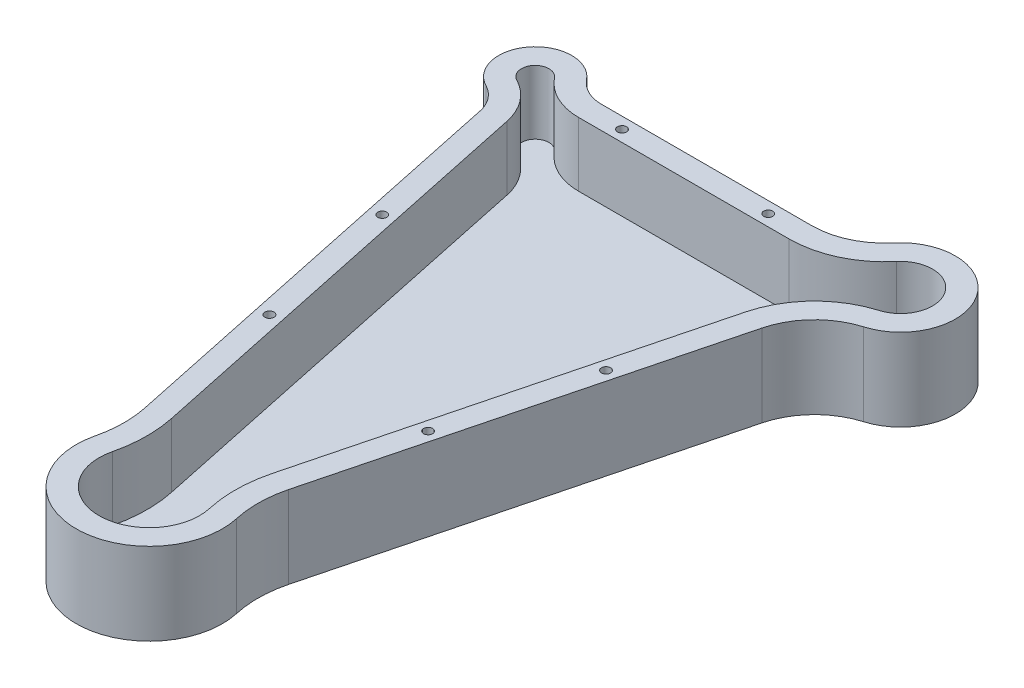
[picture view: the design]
ISO-10303-21;
HEADER;
FILE_DESCRIPTION(('STEP AP214'),'2;1');
FILE_NAME('part.step','',(''),(''),'','','');
FILE_SCHEMA(('AUTOMOTIVE_DESIGN { 1 0 10303 214 1 1 1 1 }'));
ENDSEC;
DATA;
#1=APPLICATION_CONTEXT('core data for automotive mechanical design processes');
#2=APPLICATION_PROTOCOL_DEFINITION('international standard','automotive_design',2000,#1);
#3=PRODUCT_CONTEXT('',#1,'mechanical');
#4=PRODUCT('Part','Part','',(#3));
#5=PRODUCT_RELATED_PRODUCT_CATEGORY('part','',(#4));
#6=PRODUCT_DEFINITION_FORMATION('','',#4);
#7=PRODUCT_DEFINITION_CONTEXT('part definition',#1,'design');
#8=PRODUCT_DEFINITION('design','',#6,#7);
#9=PRODUCT_DEFINITION_SHAPE('','',#8);
#10=(LENGTH_UNIT() NAMED_UNIT(*) SI_UNIT(.MILLI.,.METRE.));
#11=(NAMED_UNIT(*) PLANE_ANGLE_UNIT() SI_UNIT($,.RADIAN.));
#12=(NAMED_UNIT(*) SI_UNIT($,.STERADIAN.) SOLID_ANGLE_UNIT());
#13=UNCERTAINTY_MEASURE_WITH_UNIT(LENGTH_MEASURE(1.E-05),#10,'distance_accuracy_value','');
#14=(GEOMETRIC_REPRESENTATION_CONTEXT(3) GLOBAL_UNCERTAINTY_ASSIGNED_CONTEXT((#13)) GLOBAL_UNIT_ASSIGNED_CONTEXT((#10,
#11,#12)) REPRESENTATION_CONTEXT('',''));
#15=CARTESIAN_POINT('',(0.,0.,0.));
#16=DIRECTION('',(0.,0.,1.));
#17=DIRECTION('',(1.,0.,0.));
#18=AXIS2_PLACEMENT_3D('',#15,#16,#17);
#19=CARTESIAN_POINT('',(-73.1240495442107,12.7,-174.662274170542));
#20=DIRECTION('',(0.,-1.,0.));
#21=DIRECTION('',(0.,0.,-1.));
#22=AXIS2_PLACEMENT_3D('',#19,#20,#21);
#23=CYLINDRICAL_SURFACE('',#22,25.4);
#24=CARTESIAN_POINT('',(-73.1240495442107,0.,-174.662274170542));
#25=DIRECTION('',(0.,-1.,0.));
#26=DIRECTION('',(0.,0.,1.));
#27=AXIS2_PLACEMENT_3D('',#24,#25,#26);
#28=CIRCLE('',#27,25.4);
#29=CARTESIAN_POINT('',(-73.1240495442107,0.,-149.262274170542));
#30=VERTEX_POINT('',#29);
#31=CARTESIAN_POINT('',(-92.9519181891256,0.,-158.787274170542));
#32=VERTEX_POINT('',#31);
#33=EDGE_CURVE('E474',#30,#32,#28,.T.);
#34=ORIENTED_EDGE('',*,*,#33,.T.);
#35=DIRECTION('',(0.,-1.,0.));
#36=VECTOR('',#35,1.);
#37=CARTESIAN_POINT('',(-92.9519181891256,12.7,-158.787274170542));
#38=LINE('',#37,#36);
#39=CARTESIAN_POINT('',(-92.9519181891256,57.15,-158.787274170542));
#40=VERTEX_POINT('',#39);
#41=EDGE_CURVE('E12',#40,#32,#38,.T.);
#42=ORIENTED_EDGE('',*,*,#41,.F.);
#43=CARTESIAN_POINT('',(-73.1240495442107,57.15,-174.662274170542));
#44=DIRECTION('',(0.,-1.,0.));
#45=DIRECTION('',(0.,0.,1.));
#46=AXIS2_PLACEMENT_3D('',#43,#44,#45);
#47=CIRCLE('',#46,25.4);
#48=CARTESIAN_POINT('',(-73.1240495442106,57.15,-149.262274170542));
#49=VERTEX_POINT('',#48);
#50=EDGE_CURVE('E471',#49,#40,#47,.T.);
#51=ORIENTED_EDGE('',*,*,#50,.F.);
#52=DIRECTION('',(0.,-1.,0.));
#53=VECTOR('',#52,1.);
#54=CARTESIAN_POINT('',(-73.1240495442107,12.7,-149.262274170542));
#55=LINE('',#54,#53);
#56=EDGE_CURVE('E499',#49,#30,#55,.T.);
#57=ORIENTED_EDGE('',*,*,#56,.T.);
#58=EDGE_LOOP('',(#34,#42,#51,#57));
#59=FACE_BOUND('',#58,.T.);
#60=ADVANCED_FACE('F105',(#59),#23,.F.);
#61=CARTESIAN_POINT('',(-112.77978683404,12.7,-142.912274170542));
#62=DIRECTION('',(0.,-1.,0.));
#63=DIRECTION('',(0.,0.,-1.));
#64=AXIS2_PLACEMENT_3D('',#61,#62,#63);
#65=CYLINDRICAL_SURFACE('',#64,25.4);
#66=CARTESIAN_POINT('',(-112.77978683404,0.,-142.912274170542));
#67=DIRECTION('',(0.,1.,0.));
#68=DIRECTION('',(0.,0.,-1.));
#69=AXIS2_PLACEMENT_3D('',#66,#67,#68);
#70=CIRCLE('',#69,25.4);
#71=CARTESIAN_POINT('',(-124.432703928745,0.,-120.343057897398));
#72=VERTEX_POINT('',#71);
#73=EDGE_CURVE('E477',#32,#72,#70,.T.);
#74=ORIENTED_EDGE('',*,*,#73,.T.);
#75=DIRECTION('',(0.,-1.,0.));
#76=VECTOR('',#75,1.);
#77=CARTESIAN_POINT('',(-124.432703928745,12.7,-120.343057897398));
#78=LINE('',#77,#76);
#79=CARTESIAN_POINT('',(-124.432703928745,57.15,-120.343057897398));
#80=VERTEX_POINT('',#79);
#81=EDGE_CURVE('E112',#80,#72,#78,.T.);
#82=ORIENTED_EDGE('',*,*,#81,.F.);
#83=CARTESIAN_POINT('',(-112.77978683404,57.15,-142.912274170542));
#84=DIRECTION('',(0.,1.,0.));
#85=DIRECTION('',(0.,0.,1.));
#86=AXIS2_PLACEMENT_3D('',#83,#84,#85);
#87=CIRCLE('',#86,25.4);
#88=EDGE_CURVE('E438',#40,#80,#87,.T.);
#89=ORIENTED_EDGE('',*,*,#88,.F.);
#90=ORIENTED_EDGE('',*,*,#41,.T.);
#91=EDGE_LOOP('',(#74,#82,#89,#90));
#92=FACE_BOUND('',#91,.T.);
#93=ADVANCED_FACE('F579',(#92),#65,.T.);
#94=CARTESIAN_POINT('',(-136.08562102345,12.7,-97.7738416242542));
#95=DIRECTION('',(0.,-1.,0.));
#96=DIRECTION('',(0.,0.,-1.));
#97=AXIS2_PLACEMENT_3D('',#94,#95,#96);
#98=CYLINDRICAL_SURFACE('',#97,25.4);
#99=CARTESIAN_POINT('',(-136.08562102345,0.,-97.7738416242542));
#100=DIRECTION('',(0.,-1.,0.));
#101=DIRECTION('',(0.,0.,-1.));
#102=AXIS2_PLACEMENT_3D('',#99,#100,#101);
#103=CIRCLE('',#102,25.4);
#104=CARTESIAN_POINT('',(-111.23256360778,0.,-103.016506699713));
#105=VERTEX_POINT('',#104);
#106=EDGE_CURVE('E479',#72,#105,#103,.T.);
#107=ORIENTED_EDGE('',*,*,#106,.T.);
#108=DIRECTION('',(0.,-1.,0.));
#109=VECTOR('',#108,1.);
#110=CARTESIAN_POINT('',(-111.23256360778,12.7,-103.016506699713));
#111=LINE('',#110,#109);
#112=CARTESIAN_POINT('',(-111.23256360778,57.15,-103.016506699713));
#113=VERTEX_POINT('',#112);
#114=EDGE_CURVE('E526',#113,#105,#111,.T.);
#115=ORIENTED_EDGE('',*,*,#114,.F.);
#116=CARTESIAN_POINT('',(-136.08562102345,57.15,-97.7738416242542));
#117=DIRECTION('',(0.,-1.,0.));
#118=DIRECTION('',(0.,0.,1.));
#119=AXIS2_PLACEMENT_3D('',#116,#117,#118);
#120=CIRCLE('',#119,25.4);
#121=EDGE_CURVE('E441',#80,#113,#120,.T.);
#122=ORIENTED_EDGE('',*,*,#121,.F.);
#123=ORIENTED_EDGE('',*,*,#81,.T.);
#124=EDGE_LOOP('',(#107,#115,#122,#123));
#125=FACE_BOUND('',#124,.T.);
#126=ADVANCED_FACE('F532',(#125),#98,.F.);
#127=CARTESIAN_POINT('',(-111.23256360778,12.7,-103.016506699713));
#128=DIRECTION('',(0.978466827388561,0.,-0.206404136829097));
#129=DIRECTION('',(-0.206404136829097,0.,-0.978466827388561));
#130=AXIS2_PLACEMENT_3D('',#127,#128,#129);
#131=PLANE('',#130);
#132=DIRECTION('',(0.206404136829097,0.,0.978466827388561));
#133=VECTOR('',#132,1.);
#134=CARTESIAN_POINT('',(-111.23256360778,0.,-103.016506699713));
#135=LINE('',#134,#133);
#136=CARTESIAN_POINT('',(-48.879605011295,0.,192.570115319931));
#137=VERTEX_POINT('',#136);
#138=EDGE_CURVE('E481',#105,#137,#135,.T.);
#139=ORIENTED_EDGE('',*,*,#138,.T.);
#140=DIRECTION('',(0.,-1.,0.));
#141=VECTOR('',#140,1.);
#142=CARTESIAN_POINT('',(-48.879605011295,12.7,192.570115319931));
#143=LINE('',#142,#141);
#144=CARTESIAN_POINT('',(-48.879605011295,57.15,192.570115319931));
#145=VERTEX_POINT('',#144);
#146=EDGE_CURVE('E523',#145,#137,#143,.T.);
#147=ORIENTED_EDGE('',*,*,#146,.F.);
#148=DIRECTION('',(0.206404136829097,0.,0.978466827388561));
#149=VECTOR('',#148,1.);
#150=CARTESIAN_POINT('',(-111.23256360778,57.15,-103.016506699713));
#151=LINE('',#150,#149);
#152=EDGE_CURVE('E444',#113,#145,#151,.T.);
#153=ORIENTED_EDGE('',*,*,#152,.F.);
#154=ORIENTED_EDGE('',*,*,#114,.T.);
#155=EDGE_LOOP('',(#139,#147,#153,#154));
#156=FACE_BOUND('',#155,.T.);
#157=ADVANCED_FACE('F542',(#156),#131,.F.);
#158=CARTESIAN_POINT('',(-123.438777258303,12.7,208.298110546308));
#159=DIRECTION('',(0.,-1.,0.));
#160=DIRECTION('',(0.,0.,-1.));
#161=AXIS2_PLACEMENT_3D('',#158,#159,#160);
#162=CYLINDRICAL_SURFACE('',#161,76.2);
#163=CARTESIAN_POINT('',(-123.438777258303,0.,208.298110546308));
#164=DIRECTION('',(0.,-1.,0.));
#165=DIRECTION('',(0.,0.,1.));
#166=AXIS2_PLACEMENT_3D('',#163,#164,#165);
#167=CIRCLE('',#166,76.2);
#168=CARTESIAN_POINT('',(-49.3755109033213,0.,226.216608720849));
#169=VERTEX_POINT('',#168);
#170=EDGE_CURVE('E483',#137,#169,#167,.T.);
#171=ORIENTED_EDGE('',*,*,#170,.T.);
#172=DIRECTION('',(0.,-1.,0.));
#173=VECTOR('',#172,1.);
#174=CARTESIAN_POINT('',(-49.3755109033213,12.7,226.216608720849));
#175=LINE('',#174,#173);
#176=CARTESIAN_POINT('',(-49.3755109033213,57.15,226.216608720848));
#177=VERTEX_POINT('',#176);
#178=EDGE_CURVE('E520',#177,#169,#175,.T.);
#179=ORIENTED_EDGE('',*,*,#178,.F.);
#180=CARTESIAN_POINT('',(-123.438777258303,57.15,208.298110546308));
#181=DIRECTION('',(0.,-1.,0.));
#182=DIRECTION('',(0.,0.,1.));
#183=AXIS2_PLACEMENT_3D('',#180,#181,#182);
#184=CIRCLE('',#183,76.2);
#185=EDGE_CURVE('E447',#145,#177,#184,.T.);
#186=ORIENTED_EDGE('',*,*,#185,.F.);
#187=ORIENTED_EDGE('',*,*,#146,.T.);
#188=EDGE_LOOP('',(#171,#179,#186,#187));
#189=FACE_BOUND('',#188,.T.);
#190=ADVANCED_FACE('F546',(#189),#162,.F.);
#191=CARTESIAN_POINT('',(0.,12.7,238.162274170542));
#192=DIRECTION('',(0.,-1.,0.));
#193=DIRECTION('',(0.,0.,-1.));
#194=AXIS2_PLACEMENT_3D('',#191,#192,#193);
#195=CYLINDRICAL_SURFACE('',#194,50.8);
#196=CARTESIAN_POINT('',(0.,0.,238.162274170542));
#197=DIRECTION('',(0.,1.,0.));
#198=DIRECTION('',(0.,0.,-1.));
#199=AXIS2_PLACEMENT_3D('',#196,#197,#198);
#200=CIRCLE('',#199,50.8);
#201=CARTESIAN_POINT('',(49.5738798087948,0.,227.068562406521));
#202=VERTEX_POINT('',#201);
#203=EDGE_CURVE('E485',#169,#202,#200,.T.);
#204=ORIENTED_EDGE('',*,*,#203,.T.);
#205=DIRECTION('',(0.,-1.,0.));
#206=VECTOR('',#205,1.);
#207=CARTESIAN_POINT('',(49.5738798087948,12.7,227.068562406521));
#208=LINE('',#207,#206);
#209=CARTESIAN_POINT('',(49.5738798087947,57.15,227.068562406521));
#210=VERTEX_POINT('',#209);
#211=EDGE_CURVE('E517',#210,#202,#208,.T.);
#212=ORIENTED_EDGE('',*,*,#211,.F.);
#213=CARTESIAN_POINT('',(0.,57.15,238.162274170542));
#214=DIRECTION('',(0.,1.,0.));
#215=DIRECTION('',(0.,0.,1.));
#216=AXIS2_PLACEMENT_3D('',#213,#214,#215);
#217=CIRCLE('',#216,50.8);
#218=EDGE_CURVE('E450',#177,#210,#217,.T.);
#219=ORIENTED_EDGE('',*,*,#218,.F.);
#220=ORIENTED_EDGE('',*,*,#178,.T.);
#221=EDGE_LOOP('',(#204,#212,#219,#220));
#222=FACE_BOUND('',#221,.T.);
#223=ADVANCED_FACE('F553',(#222),#195,.T.);
#224=CARTESIAN_POINT('',(123.934699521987,12.7,210.42799476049));
#225=DIRECTION('',(0.,-1.,0.));
#226=DIRECTION('',(0.,0.,-1.));
#227=AXIS2_PLACEMENT_3D('',#224,#225,#226);
#228=CYLINDRICAL_SURFACE('',#227,76.2);
#229=CARTESIAN_POINT('',(123.934699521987,0.,210.42799476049));
#230=DIRECTION('',(0.,-1.,0.));
#231=DIRECTION('',(0.,0.,-1.));
#232=AXIS2_PLACEMENT_3D('',#229,#230,#231);
#233=CIRCLE('',#232,76.2);
#234=CARTESIAN_POINT('',(50.134019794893,0.,191.456972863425));
#235=VERTEX_POINT('',#234);
#236=EDGE_CURVE('E487',#202,#235,#233,.T.);
#237=ORIENTED_EDGE('',*,*,#236,.T.);
#238=DIRECTION('',(0.,-1.,0.));
#239=VECTOR('',#238,1.);
#240=CARTESIAN_POINT('',(50.134019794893,12.7,191.456972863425));
#241=LINE('',#240,#239);
#242=CARTESIAN_POINT('',(50.134019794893,57.15,191.456972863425));
#243=VERTEX_POINT('',#242);
#244=EDGE_CURVE('E514',#243,#235,#241,.T.);
#245=ORIENTED_EDGE('',*,*,#244,.F.);
#246=CARTESIAN_POINT('',(123.934699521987,57.15,210.42799476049));
#247=DIRECTION('',(0.,-1.,0.));
#248=DIRECTION('',(0.,0.,1.));
#249=AXIS2_PLACEMENT_3D('',#246,#247,#248);
#250=CIRCLE('',#249,76.2);
#251=EDGE_CURVE('E453',#210,#243,#250,.T.);
#252=ORIENTED_EDGE('',*,*,#251,.F.);
#253=ORIENTED_EDGE('',*,*,#211,.T.);
#254=EDGE_LOOP('',(#237,#245,#252,#253));
#255=FACE_BOUND('',#254,.T.);
#256=ADVANCED_FACE('F556',(#255),#228,.F.);
#257=CARTESIAN_POINT('',(50.1340197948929,12.7,191.456972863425));
#258=DIRECTION('',(-0.968512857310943,0.,-0.248963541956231));
#259=DIRECTION('',(-0.248963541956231,0.,0.968512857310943));
#260=AXIS2_PLACEMENT_3D('',#257,#258,#259);
#261=PLANE('',#260);
#262=DIRECTION('',(0.248963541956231,0.,-0.968512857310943));
#263=VECTOR('',#262,1.);
#264=CARTESIAN_POINT('',(50.1340197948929,0.,191.456972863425));
#265=LINE('',#264,#263);
#266=CARTESIAN_POINT('',(117.438914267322,0.,-70.3711451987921));
#267=VERTEX_POINT('',#266);
#268=EDGE_CURVE('E489',#235,#267,#265,.T.);
#269=ORIENTED_EDGE('',*,*,#268,.T.);
#270=DIRECTION('',(0.,-1.,0.));
#271=VECTOR('',#270,1.);
#272=CARTESIAN_POINT('',(117.438914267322,12.7,-70.3711451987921));
#273=LINE('',#272,#271);
#274=CARTESIAN_POINT('',(117.438914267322,57.15,-70.3711451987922));
#275=VERTEX_POINT('',#274);
#276=EDGE_CURVE('E511',#275,#267,#273,.T.);
#277=ORIENTED_EDGE('',*,*,#276,.F.);
#278=DIRECTION('',(0.248963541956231,0.,-0.968512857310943));
#279=VECTOR('',#278,1.);
#280=CARTESIAN_POINT('',(50.134019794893,57.15,191.456972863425));
#281=LINE('',#280,#279);
#282=EDGE_CURVE('E456',#243,#275,#281,.T.);
#283=ORIENTED_EDGE('',*,*,#282,.F.);
#284=ORIENTED_EDGE('',*,*,#244,.T.);
#285=EDGE_LOOP('',(#269,#277,#283,#284));
#286=FACE_BOUND('',#285,.T.);
#287=ADVANCED_FACE('F561',(#286),#261,.F.);
#288=CARTESIAN_POINT('',(166.639367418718,12.7,-57.7237972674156));
#289=DIRECTION('',(0.,-1.,0.));
#290=DIRECTION('',(0.,0.,-1.));
#291=AXIS2_PLACEMENT_3D('',#288,#289,#290);
#292=CYLINDRICAL_SURFACE('',#291,50.8);
#293=CARTESIAN_POINT('',(166.639367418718,0.,-57.7237972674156));
#294=DIRECTION('',(0.,-1.,0.));
#295=DIRECTION('',(0.,0.,1.));
#296=AXIS2_PLACEMENT_3D('',#293,#294,#295);
#297=CIRCLE('',#296,50.8);
#298=CARTESIAN_POINT('',(152.114136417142,0.,-106.402926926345));
#299=VERTEX_POINT('',#298);
#300=EDGE_CURVE('E491',#267,#299,#297,.T.);
#301=ORIENTED_EDGE('',*,*,#300,.T.);
#302=DIRECTION('',(0.,-1.,0.));
#303=VECTOR('',#302,1.);
#304=CARTESIAN_POINT('',(152.114136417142,12.7,-106.402926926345));
#305=LINE('',#304,#303);
#306=CARTESIAN_POINT('',(152.114136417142,57.15,-106.402926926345));
#307=VERTEX_POINT('',#306);
#308=EDGE_CURVE('E508',#307,#299,#305,.T.);
#309=ORIENTED_EDGE('',*,*,#308,.F.);
#310=CARTESIAN_POINT('',(166.639367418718,57.15,-57.7237972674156));
#311=DIRECTION('',(0.,-1.,0.));
#312=DIRECTION('',(0.,0.,1.));
#313=AXIS2_PLACEMENT_3D('',#310,#311,#312);
#314=CIRCLE('',#313,50.8);
#315=EDGE_CURVE('E459',#275,#307,#314,.T.);
#316=ORIENTED_EDGE('',*,*,#315,.F.);
#317=ORIENTED_EDGE('',*,*,#276,.T.);
#318=EDGE_LOOP('',(#301,#309,#316,#317));
#319=FACE_BOUND('',#318,.T.);
#320=ADVANCED_FACE('F565',(#319),#292,.F.);
#321=CARTESIAN_POINT('',(141.22021316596,12.7,-142.912274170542));
#322=DIRECTION('',(0.,-1.,0.));
#323=DIRECTION('',(0.,0.,-1.));
#324=AXIS2_PLACEMENT_3D('',#321,#322,#323);
#325=CYLINDRICAL_SURFACE('',#324,38.1);
#326=CARTESIAN_POINT('',(141.22021316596,0.,-142.912274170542));
#327=DIRECTION('',(0.,1.,0.));
#328=DIRECTION('',(0.,0.,1.));
#329=AXIS2_PLACEMENT_3D('',#326,#327,#328);
#330=CIRCLE('',#329,38.1);
#331=CARTESIAN_POINT('',(112.036143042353,0.,-167.405131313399));
#332=VERTEX_POINT('',#331);
#333=EDGE_CURVE('E493',#299,#332,#330,.T.);
#334=ORIENTED_EDGE('',*,*,#333,.T.);
#335=DIRECTION('',(0.,-1.,0.));
#336=VECTOR('',#335,1.);
#337=CARTESIAN_POINT('',(112.036143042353,12.7,-167.405131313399));
#338=LINE('',#337,#336);
#339=CARTESIAN_POINT('',(112.036143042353,57.15,-167.405131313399));
#340=VERTEX_POINT('',#339);
#341=EDGE_CURVE('E505',#340,#332,#338,.T.);
#342=ORIENTED_EDGE('',*,*,#341,.F.);
#343=CARTESIAN_POINT('',(141.22021316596,57.15,-142.912274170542));
#344=DIRECTION('',(0.,1.,0.));
#345=DIRECTION('',(0.,0.,1.));
#346=AXIS2_PLACEMENT_3D('',#343,#344,#345);
#347=CIRCLE('',#346,38.1);
#348=EDGE_CURVE('E462',#307,#340,#347,.T.);
#349=ORIENTED_EDGE('',*,*,#348,.F.);
#350=ORIENTED_EDGE('',*,*,#308,.T.);
#351=EDGE_LOOP('',(#334,#342,#349,#350));
#352=FACE_BOUND('',#351,.T.);
#353=ADVANCED_FACE('F569',(#352),#325,.T.);
#354=CARTESIAN_POINT('',(73.1240495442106,12.7,-200.062274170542));
#355=DIRECTION('',(0.,-1.,0.));
#356=DIRECTION('',(0.,0.,-1.));
#357=AXIS2_PLACEMENT_3D('',#354,#355,#356);
#358=CYLINDRICAL_SURFACE('',#357,50.8);
#359=CARTESIAN_POINT('',(73.1240495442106,0.,-200.062274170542));
#360=DIRECTION('',(0.,-1.,0.));
#361=DIRECTION('',(0.,0.,-1.));
#362=AXIS2_PLACEMENT_3D('',#359,#360,#361);
#363=CIRCLE('',#362,50.8);
#364=CARTESIAN_POINT('',(73.1240495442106,0.,-149.262274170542));
#365=VERTEX_POINT('',#364);
#366=EDGE_CURVE('E495',#332,#365,#363,.T.);
#367=ORIENTED_EDGE('',*,*,#366,.T.);
#368=DIRECTION('',(0.,-1.,0.));
#369=VECTOR('',#368,1.);
#370=CARTESIAN_POINT('',(73.1240495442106,12.7,-149.262274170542));
#371=LINE('',#370,#369);
#372=CARTESIAN_POINT('',(73.1240495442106,57.15,-149.262274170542));
#373=VERTEX_POINT('',#372);
#374=EDGE_CURVE('E502',#373,#365,#371,.T.);
#375=ORIENTED_EDGE('',*,*,#374,.F.);
#376=CARTESIAN_POINT('',(73.1240495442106,57.15,-200.062274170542));
#377=DIRECTION('',(0.,-1.,0.));
#378=DIRECTION('',(0.,0.,1.));
#379=AXIS2_PLACEMENT_3D('',#376,#377,#378);
#380=CIRCLE('',#379,50.8);
#381=EDGE_CURVE('E465',#340,#373,#380,.T.);
#382=ORIENTED_EDGE('',*,*,#381,.F.);
#383=ORIENTED_EDGE('',*,*,#341,.T.);
#384=EDGE_LOOP('',(#367,#375,#382,#383));
#385=FACE_BOUND('',#384,.T.);
#386=ADVANCED_FACE('F572',(#385),#358,.F.);
#387=CARTESIAN_POINT('',(73.1240495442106,12.7,-149.262274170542));
#388=DIRECTION('',(0.,0.,1.));
#389=DIRECTION('',(1.,0.,0.));
#390=AXIS2_PLACEMENT_3D('',#387,#388,#389);
#391=PLANE('',#390);
#392=DIRECTION('',(-1.,0.,0.));
#393=VECTOR('',#392,1.);
#394=CARTESIAN_POINT('',(73.1240495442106,0.,-149.262274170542));
#395=LINE('',#394,#393);
#396=EDGE_CURVE('E497',#365,#30,#395,.T.);
#397=ORIENTED_EDGE('',*,*,#396,.T.);
#398=ORIENTED_EDGE('',*,*,#56,.F.);
#399=DIRECTION('',(-1.,0.,0.));
#400=VECTOR('',#399,1.);
#401=CARTESIAN_POINT('',(73.1240495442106,57.15,-149.262274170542));
#402=LINE('',#401,#400);
#403=EDGE_CURVE('E468',#373,#49,#402,.T.);
#404=ORIENTED_EDGE('',*,*,#403,.F.);
#405=ORIENTED_EDGE('',*,*,#374,.T.);
#406=EDGE_LOOP('',(#397,#398,#404,#405));
#407=FACE_BOUND('',#406,.T.);
#408=ADVANCED_FACE('F575',(#407),#391,.F.);
#409=CARTESIAN_POINT('',(-73.1240495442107,0.,-174.662274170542));
#410=DIRECTION('',(0.,1.,0.));
#411=DIRECTION('',(0.,0.,1.));
#412=AXIS2_PLACEMENT_3D('',#409,#410,#411);
#413=PLANE('',#412);
#414=ORIENTED_EDGE('',*,*,#33,.F.);
#415=ORIENTED_EDGE('',*,*,#396,.F.);
#416=ORIENTED_EDGE('',*,*,#366,.F.);
#417=ORIENTED_EDGE('',*,*,#333,.F.);
#418=ORIENTED_EDGE('',*,*,#300,.F.);
#419=ORIENTED_EDGE('',*,*,#268,.F.);
#420=ORIENTED_EDGE('',*,*,#236,.F.);
#421=ORIENTED_EDGE('',*,*,#203,.F.);
#422=ORIENTED_EDGE('',*,*,#170,.F.);
#423=ORIENTED_EDGE('',*,*,#138,.F.);
#424=ORIENTED_EDGE('',*,*,#106,.F.);
#425=ORIENTED_EDGE('',*,*,#73,.F.);
#426=EDGE_LOOP('',(#414,#415,#416,#417,#418,#419,#420,#421,#422,#423,#424,#425));
#427=FACE_BOUND('',#426,.T.);
#428=ADVANCED_FACE('F538',(#427),#413,.F.);
#429=CARTESIAN_POINT('',(-112.77978683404,57.15,-142.912274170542));
#430=DIRECTION('',(0.,1.,0.));
#431=DIRECTION('',(0.,0.,1.));
#432=AXIS2_PLACEMENT_3D('',#429,#430,#431);
#433=PLANE('',#432);
#434=CARTESIAN_POINT('',(-50.8,57.15,-141.324774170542));
#435=DIRECTION('',(0.,1.,0.));
#436=DIRECTION('',(0.,0.,1.));
#437=AXIS2_PLACEMENT_3D('',#434,#435,#436);
#438=CIRCLE('',#437,3.17499999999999);
#439=CARTESIAN_POINT('',(-50.8,57.15,-138.149774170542));
#440=VERTEX_POINT('',#439);
#441=EDGE_CURVE('E756',#440,#440,#438,.T.);
#442=ORIENTED_EDGE('',*,*,#441,.F.);
#443=EDGE_LOOP('',(#442));
#444=FACE_BOUND('',#443,.T.);
#445=CARTESIAN_POINT('',(50.8,57.15,-141.324774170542));
#446=DIRECTION('',(0.,1.,0.));
#447=DIRECTION('',(0.,0.,1.));
#448=AXIS2_PLACEMENT_3D('',#445,#446,#447);
#449=CIRCLE('',#448,3.175);
#450=CARTESIAN_POINT('',(50.8,57.15,-138.149774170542));
#451=VERTEX_POINT('',#450);
#452=EDGE_CURVE('E289',#451,#451,#449,.T.);
#453=ORIENTED_EDGE('',*,*,#452,.F.);
#454=EDGE_LOOP('',(#453));
#455=FACE_BOUND('',#454,.T.);
#456=CARTESIAN_POINT('',(88.7462441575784,57.15,9.3663125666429));
#457=DIRECTION('',(0.,1.,0.));
#458=DIRECTION('',(0.,0.,1.));
#459=AXIS2_PLACEMENT_3D('',#456,#457,#458);
#460=CIRCLE('',#459,3.175);
#461=CARTESIAN_POINT('',(88.7462441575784,57.15,12.5413125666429));
#462=VERTEX_POINT('',#461);
#463=EDGE_CURVE('E308',#462,#462,#460,.T.);
#464=ORIENTED_EDGE('',*,*,#463,.F.);
#465=EDGE_LOOP('',(#464));
#466=FACE_BOUND('',#465,.T.);
#467=CARTESIAN_POINT('',(63.4515482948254,57.15,107.767218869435));
#468=DIRECTION('',(0.,1.,0.));
#469=DIRECTION('',(0.,0.,1.));
#470=AXIS2_PLACEMENT_3D('',#467,#468,#469);
#471=CIRCLE('',#470,3.175);
#472=CARTESIAN_POINT('',(63.4515482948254,57.15,110.942218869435));
#473=VERTEX_POINT('',#472);
#474=EDGE_CURVE('E320',#473,#473,#471,.T.);
#475=ORIENTED_EDGE('',*,*,#474,.F.);
#476=EDGE_LOOP('',(#475));
#477=FACE_BOUND('',#476,.T.);
#478=CARTESIAN_POINT('',(-61.8041737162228,57.15,92.8445863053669));
#479=DIRECTION('',(0.,1.,0.));
#480=DIRECTION('',(0.,0.,1.));
#481=AXIS2_PLACEMENT_3D('',#478,#479,#480);
#482=CIRCLE('',#481,3.175);
#483=CARTESIAN_POINT('',(-61.8041737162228,57.15,96.0195863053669));
#484=VERTEX_POINT('',#483);
#485=EDGE_CURVE('E332',#484,#484,#482,.T.);
#486=ORIENTED_EDGE('',*,*,#485,.F.);
#487=EDGE_LOOP('',(#486));
#488=FACE_BOUND('',#487,.T.);
#489=CARTESIAN_POINT('',(-82.7748340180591,57.15,-6.5676433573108));
#490=DIRECTION('',(0.,1.,0.));
#491=DIRECTION('',(0.,0.,1.));
#492=AXIS2_PLACEMENT_3D('',#489,#490,#491);
#493=CIRCLE('',#492,3.175);
#494=CARTESIAN_POINT('',(-82.7748340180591,57.15,-3.39264335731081));
#495=VERTEX_POINT('',#494);
#496=EDGE_CURVE('E344',#495,#495,#493,.T.);
#497=ORIENTED_EDGE('',*,*,#496,.F.);
#498=EDGE_LOOP('',(#497));
#499=FACE_BOUND('',#498,.T.);
#500=ORIENTED_EDGE('',*,*,#88,.T.);
#501=ORIENTED_EDGE('',*,*,#121,.T.);
#502=ORIENTED_EDGE('',*,*,#152,.T.);
#503=ORIENTED_EDGE('',*,*,#185,.T.);
#504=ORIENTED_EDGE('',*,*,#218,.T.);
#505=ORIENTED_EDGE('',*,*,#251,.T.);
#506=ORIENTED_EDGE('',*,*,#282,.T.);
#507=ORIENTED_EDGE('',*,*,#315,.T.);
#508=ORIENTED_EDGE('',*,*,#348,.T.);
#509=ORIENTED_EDGE('',*,*,#381,.T.);
#510=ORIENTED_EDGE('',*,*,#403,.T.);
#511=ORIENTED_EDGE('',*,*,#50,.T.);
#512=EDGE_LOOP('',(#500,#501,#502,#503,#504,#505,#506,#507,#508,#509,#510,#511));
#513=FACE_BOUND('',#512,.T.);
#514=CARTESIAN_POINT('',(-136.08562102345,57.15,-97.7738416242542));
#515=DIRECTION('',(0.,1.,0.));
#516=DIRECTION('',(-1.,0.,0.));
#517=AXIS2_PLACEMENT_3D('',#514,#515,#516);
#518=CIRCLE('',#517,41.275);
#519=CARTESIAN_POINT('',(-117.149630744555,57.15,-134.448818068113));
#520=VERTEX_POINT('',#519);
#521=CARTESIAN_POINT('',(-95.6994027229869,57.15,-106.293172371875));
#522=VERTEX_POINT('',#521);
#523=EDGE_CURVE('E358',#520,#522,#518,.F.);
#524=ORIENTED_EDGE('',*,*,#523,.F.);
#525=CARTESIAN_POINT('',(-112.77978683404,57.15,-142.912274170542));
#526=DIRECTION('',(0.,1.,0.));
#527=DIRECTION('',(-1.,0.,0.));
#528=AXIS2_PLACEMENT_3D('',#525,#526,#527);
#529=CIRCLE('',#528,9.52499999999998);
#530=CARTESIAN_POINT('',(-105.344336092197,57.15,-148.865399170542));
#531=VERTEX_POINT('',#530);
#532=EDGE_CURVE('E356',#531,#520,#529,.T.);
#533=ORIENTED_EDGE('',*,*,#532,.F.);
#534=CARTESIAN_POINT('',(-73.1240495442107,57.15,-174.662274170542));
#535=DIRECTION('',(0.,1.,0.));
#536=DIRECTION('',(-1.,0.,0.));
#537=AXIS2_PLACEMENT_3D('',#534,#535,#536);
#538=CIRCLE('',#537,41.275);
#539=CARTESIAN_POINT('',(-73.1240495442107,57.15,-133.387274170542));
#540=VERTEX_POINT('',#539);
#541=EDGE_CURVE('E380',#540,#531,#538,.F.);
#542=ORIENTED_EDGE('',*,*,#541,.F.);
#543=DIRECTION('',(-1.,0.,0.));
#544=VECTOR('',#543,1.);
#545=CARTESIAN_POINT('',(73.1240495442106,57.15,-133.387274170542));
#546=LINE('',#545,#544);
#547=CARTESIAN_POINT('',(73.1240495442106,57.15,-133.387274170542));
#548=VERTEX_POINT('',#547);
#549=EDGE_CURVE('E377',#548,#540,#546,.T.);
#550=ORIENTED_EDGE('',*,*,#549,.F.);
#551=CARTESIAN_POINT('',(73.1240495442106,57.15,-200.062274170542));
#552=DIRECTION('',(0.,1.,0.));
#553=DIRECTION('',(-1.,0.,0.));
#554=AXIS2_PLACEMENT_3D('',#551,#552,#553);
#555=CIRCLE('',#554,66.675);
#556=CARTESIAN_POINT('',(124.196172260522,57.15,-157.199774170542));
#557=VERTEX_POINT('',#556);
#558=EDGE_CURVE('E375',#557,#548,#555,.F.);
#559=ORIENTED_EDGE('',*,*,#558,.F.);
#560=CARTESIAN_POINT('',(141.22021316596,57.15,-142.912274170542));
#561=DIRECTION('',(0.,1.,0.));
#562=DIRECTION('',(-1.,0.,0.));
#563=AXIS2_PLACEMENT_3D('',#560,#561,#562);
#564=CIRCLE('',#563,22.225);
#565=CARTESIAN_POINT('',(147.575001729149,57.15,-121.61515494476));
#566=VERTEX_POINT('',#565);
#567=EDGE_CURVE('E373',#566,#557,#564,.T.);
#568=ORIENTED_EDGE('',*,*,#567,.F.);
#569=CARTESIAN_POINT('',(166.639367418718,57.15,-57.7237972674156));
#570=DIRECTION('',(0.,1.,0.));
#571=DIRECTION('',(-1.,0.,0.));
#572=AXIS2_PLACEMENT_3D('',#569,#570,#571);
#573=CIRCLE('',#572,66.675);
#574=CARTESIAN_POINT('',(102.063772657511,57.15,-74.3234414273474));
#575=VERTEX_POINT('',#574);
#576=EDGE_CURVE('E371',#575,#566,#573,.F.);
#577=ORIENTED_EDGE('',*,*,#576,.F.);
#578=DIRECTION('',(0.248963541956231,0.,-0.968512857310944));
#579=VECTOR('',#578,1.);
#580=CARTESIAN_POINT('',(34.7588781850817,57.15,187.50467663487));
#581=LINE('',#580,#579);
#582=CARTESIAN_POINT('',(34.7588781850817,57.15,187.50467663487));
#583=VERTEX_POINT('',#582);
#584=EDGE_CURVE('E369',#583,#575,#581,.T.);
#585=ORIENTED_EDGE('',*,*,#584,.F.);
#586=CARTESIAN_POINT('',(123.934699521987,57.15,210.42799476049));
#587=DIRECTION('',(0.,1.,0.));
#588=DIRECTION('',(-1.,0.,0.));
#589=AXIS2_PLACEMENT_3D('',#586,#587,#588);
#590=CIRCLE('',#589,92.075);
#591=CARTESIAN_POINT('',(34.0820423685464,57.15,230.535347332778));
#592=VERTEX_POINT('',#591);
#593=EDGE_CURVE('E367',#592,#583,#590,.F.);
#594=ORIENTED_EDGE('',*,*,#593,.F.);
#595=CARTESIAN_POINT('',(0.,57.15,238.162274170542));
#596=DIRECTION('',(0.,1.,0.));
#597=DIRECTION('',(-1.,0.,0.));
#598=AXIS2_PLACEMENT_3D('',#595,#596,#597);
#599=CIRCLE('',#598,34.925);
#600=CARTESIAN_POINT('',(-33.9456637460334,57.15,229.949629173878));
#601=VERTEX_POINT('',#600);
#602=EDGE_CURVE('E365',#601,#592,#599,.T.);
#603=ORIENTED_EDGE('',*,*,#602,.F.);
#604=CARTESIAN_POINT('',(-123.438777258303,57.15,208.298110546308));
#605=DIRECTION('',(0.,1.,0.));
#606=DIRECTION('',(-1.,0.,0.));
#607=AXIS2_PLACEMENT_3D('',#604,#605,#606);
#608=CIRCLE('',#607,92.075);
#609=CARTESIAN_POINT('',(-33.3464441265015,57.15,189.293449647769));
#610=VERTEX_POINT('',#609);
#611=EDGE_CURVE('E363',#610,#601,#608,.F.);
#612=ORIENTED_EDGE('',*,*,#611,.F.);
#613=DIRECTION('',(0.206404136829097,0.,0.978466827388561));
#614=VECTOR('',#613,1.);
#615=CARTESIAN_POINT('',(-95.6994027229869,57.15,-106.293172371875));
#616=LINE('',#615,#614);
#617=EDGE_CURVE('E361',#522,#610,#616,.T.);
#618=ORIENTED_EDGE('',*,*,#617,.F.);
#619=EDGE_LOOP('',(#524,#533,#542,#550,#559,#568,#577,#585,#594,#603,#612,#618));
#620=FACE_BOUND('',#619,.T.);
#621=ADVANCED_FACE('F549',(#444,#455,#466,#477,#488,#499,#513,#620),#433,.T.);
#622=CARTESIAN_POINT('',(-112.77978683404,57.15,-142.912274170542));
#623=DIRECTION('',(0.,-1.,0.));
#624=DIRECTION('',(0.,0.,-1.));
#625=AXIS2_PLACEMENT_3D('',#622,#623,#624);
#626=CYLINDRICAL_SURFACE('',#625,9.52499999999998);
#627=CARTESIAN_POINT('',(-112.77978683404,12.7,-142.912274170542));
#628=DIRECTION('',(0.,1.,0.));
#629=DIRECTION('',(-1.,0.,0.));
#630=AXIS2_PLACEMENT_3D('',#627,#628,#629);
#631=CIRCLE('',#630,9.52499999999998);
#632=CARTESIAN_POINT('',(-105.344336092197,12.7,-148.865399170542));
#633=VERTEX_POINT('',#632);
#634=CARTESIAN_POINT('',(-117.149630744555,12.7,-134.448818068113));
#635=VERTEX_POINT('',#634);
#636=EDGE_CURVE('E119',#633,#635,#631,.T.);
#637=ORIENTED_EDGE('',*,*,#636,.F.);
#638=DIRECTION('',(0.,-1.,0.));
#639=VECTOR('',#638,1.);
#640=CARTESIAN_POINT('',(-105.344336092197,57.15,-148.865399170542));
#641=LINE('',#640,#639);
#642=EDGE_CURVE('E382',#531,#633,#641,.T.);
#643=ORIENTED_EDGE('',*,*,#642,.F.);
#644=ORIENTED_EDGE('',*,*,#532,.T.);
#645=DIRECTION('',(0.,-1.,0.));
#646=VECTOR('',#645,1.);
#647=CARTESIAN_POINT('',(-117.149630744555,57.15,-134.448818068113));
#648=LINE('',#647,#646);
#649=EDGE_CURVE('E435',#520,#635,#648,.T.);
#650=ORIENTED_EDGE('',*,*,#649,.T.);
#651=EDGE_LOOP('',(#637,#643,#644,#650));
#652=FACE_BOUND('',#651,.T.);
#653=ADVANCED_FACE('F614',(#652),#626,.F.);
#654=CARTESIAN_POINT('',(-136.08562102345,57.15,-97.7738416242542));
#655=DIRECTION('',(0.,-1.,0.));
#656=DIRECTION('',(0.,0.,-1.));
#657=AXIS2_PLACEMENT_3D('',#654,#655,#656);
#658=CYLINDRICAL_SURFACE('',#657,41.275);
#659=CARTESIAN_POINT('',(-136.08562102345,12.7,-97.7738416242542));
#660=DIRECTION('',(0.,1.,0.));
#661=DIRECTION('',(-1.,0.,0.));
#662=AXIS2_PLACEMENT_3D('',#659,#660,#661);
#663=CIRCLE('',#662,41.275);
#664=CARTESIAN_POINT('',(-95.6994027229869,12.7,-106.293172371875));
#665=VERTEX_POINT('',#664);
#666=EDGE_CURVE('E123',#635,#665,#663,.F.);
#667=ORIENTED_EDGE('',*,*,#666,.F.);
#668=ORIENTED_EDGE('',*,*,#649,.F.);
#669=ORIENTED_EDGE('',*,*,#523,.T.);
#670=DIRECTION('',(0.,-1.,0.));
#671=VECTOR('',#670,1.);
#672=CARTESIAN_POINT('',(-95.6994027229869,57.15,-106.293172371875));
#673=LINE('',#672,#671);
#674=EDGE_CURVE('E433',#522,#665,#673,.T.);
#675=ORIENTED_EDGE('',*,*,#674,.T.);
#676=EDGE_LOOP('',(#667,#668,#669,#675));
#677=FACE_BOUND('',#676,.T.);
#678=ADVANCED_FACE('F618',(#677),#658,.T.);
#679=CARTESIAN_POINT('',(-95.6994027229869,57.15,-106.293172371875));
#680=DIRECTION('',(0.978466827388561,0.,-0.206404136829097));
#681=DIRECTION('',(-0.206404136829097,0.,-0.978466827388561));
#682=AXIS2_PLACEMENT_3D('',#679,#680,#681);
#683=PLANE('',#682);
#684=DIRECTION('',(0.206404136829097,0.,0.978466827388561));
#685=VECTOR('',#684,1.);
#686=CARTESIAN_POINT('',(-95.6994027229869,12.7,-106.293172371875));
#687=LINE('',#686,#685);
#688=CARTESIAN_POINT('',(-33.3464441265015,12.7,189.293449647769));
#689=VERTEX_POINT('',#688);
#690=EDGE_CURVE('E385',#665,#689,#687,.T.);
#691=ORIENTED_EDGE('',*,*,#690,.F.);
#692=ORIENTED_EDGE('',*,*,#674,.F.);
#693=ORIENTED_EDGE('',*,*,#617,.T.);
#694=DIRECTION('',(0.,-1.,0.));
#695=VECTOR('',#694,1.);
#696=CARTESIAN_POINT('',(-33.3464441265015,57.15,189.293449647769));
#697=LINE('',#696,#695);
#698=EDGE_CURVE('E430',#610,#689,#697,.T.);
#699=ORIENTED_EDGE('',*,*,#698,.T.);
#700=EDGE_LOOP('',(#691,#692,#693,#699));
#701=FACE_BOUND('',#700,.T.);
#702=ADVANCED_FACE('F622',(#701),#683,.T.);
#703=CARTESIAN_POINT('',(-123.438777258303,57.15,208.298110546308));
#704=DIRECTION('',(0.,-1.,0.));
#705=DIRECTION('',(0.,0.,-1.));
#706=AXIS2_PLACEMENT_3D('',#703,#704,#705);
#707=CYLINDRICAL_SURFACE('',#706,92.075);
#708=CARTESIAN_POINT('',(-123.438777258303,12.7,208.298110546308));
#709=DIRECTION('',(0.,1.,0.));
#710=DIRECTION('',(-1.,0.,0.));
#711=AXIS2_PLACEMENT_3D('',#708,#709,#710);
#712=CIRCLE('',#711,92.075);
#713=CARTESIAN_POINT('',(-33.9456637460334,12.7,229.949629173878));
#714=VERTEX_POINT('',#713);
#715=EDGE_CURVE('E387',#689,#714,#712,.F.);
#716=ORIENTED_EDGE('',*,*,#715,.F.);
#717=ORIENTED_EDGE('',*,*,#698,.F.);
#718=ORIENTED_EDGE('',*,*,#611,.T.);
#719=DIRECTION('',(0.,-1.,0.));
#720=VECTOR('',#719,1.);
#721=CARTESIAN_POINT('',(-33.9456637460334,57.15,229.949629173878));
#722=LINE('',#721,#720);
#723=EDGE_CURVE('E427',#601,#714,#722,.T.);
#724=ORIENTED_EDGE('',*,*,#723,.T.);
#725=EDGE_LOOP('',(#716,#717,#718,#724));
#726=FACE_BOUND('',#725,.T.);
#727=ADVANCED_FACE('F626',(#726),#707,.T.);
#728=CARTESIAN_POINT('',(0.,57.15,238.162274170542));
#729=DIRECTION('',(0.,-1.,0.));
#730=DIRECTION('',(0.,0.,-1.));
#731=AXIS2_PLACEMENT_3D('',#728,#729,#730);
#732=CYLINDRICAL_SURFACE('',#731,34.925);
#733=CARTESIAN_POINT('',(0.,12.7,238.162274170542));
#734=DIRECTION('',(0.,1.,0.));
#735=DIRECTION('',(-1.,0.,0.));
#736=AXIS2_PLACEMENT_3D('',#733,#734,#735);
#737=CIRCLE('',#736,34.925);
#738=CARTESIAN_POINT('',(34.0820423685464,12.7,230.535347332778));
#739=VERTEX_POINT('',#738);
#740=EDGE_CURVE('E389',#714,#739,#737,.T.);
#741=ORIENTED_EDGE('',*,*,#740,.F.);
#742=ORIENTED_EDGE('',*,*,#723,.F.);
#743=ORIENTED_EDGE('',*,*,#602,.T.);
#744=DIRECTION('',(0.,-1.,0.));
#745=VECTOR('',#744,1.);
#746=CARTESIAN_POINT('',(34.0820423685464,57.15,230.535347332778));
#747=LINE('',#746,#745);
#748=EDGE_CURVE('E424',#592,#739,#747,.T.);
#749=ORIENTED_EDGE('',*,*,#748,.T.);
#750=EDGE_LOOP('',(#741,#742,#743,#749));
#751=FACE_BOUND('',#750,.T.);
#752=ADVANCED_FACE('F630',(#751),#732,.F.);
#753=CARTESIAN_POINT('',(123.934699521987,57.15,210.42799476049));
#754=DIRECTION('',(0.,-1.,0.));
#755=DIRECTION('',(0.,0.,-1.));
#756=AXIS2_PLACEMENT_3D('',#753,#754,#755);
#757=CYLINDRICAL_SURFACE('',#756,92.075);
#758=CARTESIAN_POINT('',(123.934699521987,12.7,210.42799476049));
#759=DIRECTION('',(0.,1.,0.));
#760=DIRECTION('',(-1.,0.,0.));
#761=AXIS2_PLACEMENT_3D('',#758,#759,#760);
#762=CIRCLE('',#761,92.075);
#763=CARTESIAN_POINT('',(34.7588781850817,12.7,187.50467663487));
#764=VERTEX_POINT('',#763);
#765=EDGE_CURVE('E391',#739,#764,#762,.F.);
#766=ORIENTED_EDGE('',*,*,#765,.F.);
#767=ORIENTED_EDGE('',*,*,#748,.F.);
#768=ORIENTED_EDGE('',*,*,#593,.T.);
#769=DIRECTION('',(0.,-1.,0.));
#770=VECTOR('',#769,1.);
#771=CARTESIAN_POINT('',(34.7588781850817,57.15,187.50467663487));
#772=LINE('',#771,#770);
#773=EDGE_CURVE('E421',#583,#764,#772,.T.);
#774=ORIENTED_EDGE('',*,*,#773,.T.);
#775=EDGE_LOOP('',(#766,#767,#768,#774));
#776=FACE_BOUND('',#775,.T.);
#777=ADVANCED_FACE('F634',(#776),#757,.T.);
#778=CARTESIAN_POINT('',(34.7588781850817,57.15,187.50467663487));
#779=DIRECTION('',(-0.968512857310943,0.,-0.248963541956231));
#780=DIRECTION('',(-0.248963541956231,0.,0.968512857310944));
#781=AXIS2_PLACEMENT_3D('',#778,#779,#780);
#782=PLANE('',#781);
#783=DIRECTION('',(0.248963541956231,0.,-0.968512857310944));
#784=VECTOR('',#783,1.);
#785=CARTESIAN_POINT('',(34.7588781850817,12.7,187.50467663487));
#786=LINE('',#785,#784);
#787=CARTESIAN_POINT('',(102.063772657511,12.7,-74.3234414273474));
#788=VERTEX_POINT('',#787);
#789=EDGE_CURVE('E393',#764,#788,#786,.T.);
#790=ORIENTED_EDGE('',*,*,#789,.F.);
#791=ORIENTED_EDGE('',*,*,#773,.F.);
#792=ORIENTED_EDGE('',*,*,#584,.T.);
#793=DIRECTION('',(0.,-1.,0.));
#794=VECTOR('',#793,1.);
#795=CARTESIAN_POINT('',(102.063772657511,57.15,-74.3234414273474));
#796=LINE('',#795,#794);
#797=EDGE_CURVE('E418',#575,#788,#796,.T.);
#798=ORIENTED_EDGE('',*,*,#797,.T.);
#799=EDGE_LOOP('',(#790,#791,#792,#798));
#800=FACE_BOUND('',#799,.T.);
#801=ADVANCED_FACE('F638',(#800),#782,.T.);
#802=CARTESIAN_POINT('',(166.639367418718,57.15,-57.7237972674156));
#803=DIRECTION('',(0.,-1.,0.));
#804=DIRECTION('',(0.,0.,-1.));
#805=AXIS2_PLACEMENT_3D('',#802,#803,#804);
#806=CYLINDRICAL_SURFACE('',#805,66.675);
#807=CARTESIAN_POINT('',(166.639367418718,12.7,-57.7237972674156));
#808=DIRECTION('',(0.,1.,0.));
#809=DIRECTION('',(-1.,0.,0.));
#810=AXIS2_PLACEMENT_3D('',#807,#808,#809);
#811=CIRCLE('',#810,66.675);
#812=CARTESIAN_POINT('',(147.575001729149,12.7,-121.61515494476));
#813=VERTEX_POINT('',#812);
#814=EDGE_CURVE('E395',#788,#813,#811,.F.);
#815=ORIENTED_EDGE('',*,*,#814,.F.);
#816=ORIENTED_EDGE('',*,*,#797,.F.);
#817=ORIENTED_EDGE('',*,*,#576,.T.);
#818=DIRECTION('',(0.,-1.,0.));
#819=VECTOR('',#818,1.);
#820=CARTESIAN_POINT('',(147.575001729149,57.15,-121.61515494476));
#821=LINE('',#820,#819);
#822=EDGE_CURVE('E415',#566,#813,#821,.T.);
#823=ORIENTED_EDGE('',*,*,#822,.T.);
#824=EDGE_LOOP('',(#815,#816,#817,#823));
#825=FACE_BOUND('',#824,.T.);
#826=ADVANCED_FACE('F642',(#825),#806,.T.);
#827=CARTESIAN_POINT('',(141.22021316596,57.15,-142.912274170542));
#828=DIRECTION('',(0.,-1.,0.));
#829=DIRECTION('',(0.,0.,-1.));
#830=AXIS2_PLACEMENT_3D('',#827,#828,#829);
#831=CYLINDRICAL_SURFACE('',#830,22.225);
#832=CARTESIAN_POINT('',(141.22021316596,12.7,-142.912274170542));
#833=DIRECTION('',(0.,1.,0.));
#834=DIRECTION('',(-1.,0.,0.));
#835=AXIS2_PLACEMENT_3D('',#832,#833,#834);
#836=CIRCLE('',#835,22.225);
#837=CARTESIAN_POINT('',(124.196172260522,12.7,-157.199774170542));
#838=VERTEX_POINT('',#837);
#839=EDGE_CURVE('E397',#813,#838,#836,.T.);
#840=ORIENTED_EDGE('',*,*,#839,.F.);
#841=ORIENTED_EDGE('',*,*,#822,.F.);
#842=ORIENTED_EDGE('',*,*,#567,.T.);
#843=DIRECTION('',(0.,-1.,0.));
#844=VECTOR('',#843,1.);
#845=CARTESIAN_POINT('',(124.196172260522,57.15,-157.199774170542));
#846=LINE('',#845,#844);
#847=EDGE_CURVE('E412',#557,#838,#846,.T.);
#848=ORIENTED_EDGE('',*,*,#847,.T.);
#849=EDGE_LOOP('',(#840,#841,#842,#848));
#850=FACE_BOUND('',#849,.T.);
#851=ADVANCED_FACE('F646',(#850),#831,.F.);
#852=CARTESIAN_POINT('',(73.1240495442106,57.15,-200.062274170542));
#853=DIRECTION('',(0.,-1.,0.));
#854=DIRECTION('',(0.,0.,-1.));
#855=AXIS2_PLACEMENT_3D('',#852,#853,#854);
#856=CYLINDRICAL_SURFACE('',#855,66.675);
#857=CARTESIAN_POINT('',(73.1240495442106,12.7,-200.062274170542));
#858=DIRECTION('',(0.,1.,0.));
#859=DIRECTION('',(-1.,0.,0.));
#860=AXIS2_PLACEMENT_3D('',#857,#858,#859);
#861=CIRCLE('',#860,66.675);
#862=CARTESIAN_POINT('',(73.1240495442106,12.7,-133.387274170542));
#863=VERTEX_POINT('',#862);
#864=EDGE_CURVE('E399',#838,#863,#861,.F.);
#865=ORIENTED_EDGE('',*,*,#864,.F.);
#866=ORIENTED_EDGE('',*,*,#847,.F.);
#867=ORIENTED_EDGE('',*,*,#558,.T.);
#868=DIRECTION('',(0.,-1.,0.));
#869=VECTOR('',#868,1.);
#870=CARTESIAN_POINT('',(73.1240495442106,57.15,-133.387274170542));
#871=LINE('',#870,#869);
#872=EDGE_CURVE('E409',#548,#863,#871,.T.);
#873=ORIENTED_EDGE('',*,*,#872,.T.);
#874=EDGE_LOOP('',(#865,#866,#867,#873));
#875=FACE_BOUND('',#874,.T.);
#876=ADVANCED_FACE('F650',(#875),#856,.T.);
#877=CARTESIAN_POINT('',(73.1240495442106,57.15,-133.387274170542));
#878=DIRECTION('',(0.,0.,1.));
#879=DIRECTION('',(1.,0.,0.));
#880=AXIS2_PLACEMENT_3D('',#877,#878,#879);
#881=PLANE('',#880);
#882=DIRECTION('',(-1.,0.,0.));
#883=VECTOR('',#882,1.);
#884=CARTESIAN_POINT('',(73.1240495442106,12.7,-133.387274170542));
#885=LINE('',#884,#883);
#886=CARTESIAN_POINT('',(-73.1240495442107,12.7,-133.387274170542));
#887=VERTEX_POINT('',#886);
#888=EDGE_CURVE('E401',#863,#887,#885,.T.);
#889=ORIENTED_EDGE('',*,*,#888,.F.);
#890=ORIENTED_EDGE('',*,*,#872,.F.);
#891=ORIENTED_EDGE('',*,*,#549,.T.);
#892=DIRECTION('',(0.,-1.,0.));
#893=VECTOR('',#892,1.);
#894=CARTESIAN_POINT('',(-73.1240495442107,57.15,-133.387274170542));
#895=LINE('',#894,#893);
#896=EDGE_CURVE('E406',#540,#887,#895,.T.);
#897=ORIENTED_EDGE('',*,*,#896,.T.);
#898=EDGE_LOOP('',(#889,#890,#891,#897));
#899=FACE_BOUND('',#898,.T.);
#900=ADVANCED_FACE('F654',(#899),#881,.T.);
#901=CARTESIAN_POINT('',(-73.1240495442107,57.15,-174.662274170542));
#902=DIRECTION('',(0.,-1.,0.));
#903=DIRECTION('',(0.,0.,-1.));
#904=AXIS2_PLACEMENT_3D('',#901,#902,#903);
#905=CYLINDRICAL_SURFACE('',#904,41.275);
#906=CARTESIAN_POINT('',(-73.1240495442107,12.7,-174.662274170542));
#907=DIRECTION('',(0.,1.,0.));
#908=DIRECTION('',(-1.,0.,0.));
#909=AXIS2_PLACEMENT_3D('',#906,#907,#908);
#910=CIRCLE('',#909,41.275);
#911=EDGE_CURVE('E359',#887,#633,#910,.F.);
#912=ORIENTED_EDGE('',*,*,#911,.F.);
#913=ORIENTED_EDGE('',*,*,#896,.F.);
#914=ORIENTED_EDGE('',*,*,#541,.T.);
#915=ORIENTED_EDGE('',*,*,#642,.T.);
#916=EDGE_LOOP('',(#912,#913,#914,#915));
#917=FACE_BOUND('',#916,.T.);
#918=ADVANCED_FACE('F611',(#917),#905,.T.);
#919=CARTESIAN_POINT('',(-73.1240495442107,12.7,-174.662274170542));
#920=DIRECTION('',(0.,1.,0.));
#921=DIRECTION('',(0.,0.,1.));
#922=AXIS2_PLACEMENT_3D('',#919,#920,#921);
#923=PLANE('',#922);
#924=ORIENTED_EDGE('',*,*,#636,.T.);
#925=ORIENTED_EDGE('',*,*,#666,.T.);
#926=ORIENTED_EDGE('',*,*,#690,.T.);
#927=ORIENTED_EDGE('',*,*,#715,.T.);
#928=ORIENTED_EDGE('',*,*,#740,.T.);
#929=ORIENTED_EDGE('',*,*,#765,.T.);
#930=ORIENTED_EDGE('',*,*,#789,.T.);
#931=ORIENTED_EDGE('',*,*,#814,.T.);
#932=ORIENTED_EDGE('',*,*,#839,.T.);
#933=ORIENTED_EDGE('',*,*,#864,.T.);
#934=ORIENTED_EDGE('',*,*,#888,.T.);
#935=ORIENTED_EDGE('',*,*,#911,.T.);
#936=EDGE_LOOP('',(#924,#925,#926,#927,#928,#929,#930,#931,#932,#933,#934,#935));
#937=FACE_BOUND('',#936,.T.);
#938=ADVANCED_FACE('F607',(#937),#923,.T.);
#939=CARTESIAN_POINT('',(-82.7748340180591,41.7297108,-6.5676433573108));
#940=DIRECTION('',(0.,1.,0.));
#941=DIRECTION('',(0.,0.,1.));
#942=AXIS2_PLACEMENT_3D('',#939,#940,#941);
#943=CONICAL_SURFACE('',#942,2.7051,1.02974425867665);
#944=CARTESIAN_POINT('',(-82.7748340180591,40.1043227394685,-6.5676433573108));
#945=VERTEX_POINT('',#944);
#946=VERTEX_LOOP('',#945);
#947=FACE_BOUND('',#946,.T.);
#948=CARTESIAN_POINT('',(-82.7748340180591,41.7297108,-6.5676433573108));
#949=DIRECTION('',(0.,1.,0.));
#950=DIRECTION('',(0.,0.,1.));
#951=AXIS2_PLACEMENT_3D('',#948,#949,#950);
#952=CIRCLE('',#951,2.7051);
#953=CARTESIAN_POINT('',(-82.7748340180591,41.7297108,-3.8625433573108));
#954=VERTEX_POINT('',#953);
#955=EDGE_CURVE('E353',#954,#954,#952,.T.);
#956=ORIENTED_EDGE('',*,*,#955,.T.);
#957=EDGE_LOOP('',(#956));
#958=FACE_BOUND('',#957,.T.);
#959=ADVANCED_FACE('F610',(#947,#958),#943,.F.);
#960=CARTESIAN_POINT('',(-82.7748340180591,57.15,-6.5676433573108));
#961=DIRECTION('',(0.,1.,0.));
#962=DIRECTION('',(0.,0.,1.));
#963=AXIS2_PLACEMENT_3D('',#960,#961,#962);
#964=CYLINDRICAL_SURFACE('',#963,2.7051);
#965=ORIENTED_EDGE('',*,*,#955,.F.);
#966=EDGE_LOOP('',(#965));
#967=FACE_BOUND('',#966,.T.);
#968=CARTESIAN_POINT('',(-82.7748340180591,44.45,-6.5676433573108));
#969=DIRECTION('',(0.,1.,0.));
#970=DIRECTION('',(0.,0.,1.));
#971=AXIS2_PLACEMENT_3D('',#968,#969,#970);
#972=CIRCLE('',#971,2.7051);
#973=CARTESIAN_POINT('',(-82.7748340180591,44.45,-3.8625433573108));
#974=VERTEX_POINT('',#973);
#975=EDGE_CURVE('E350',#974,#974,#972,.T.);
#976=ORIENTED_EDGE('',*,*,#975,.T.);
#977=EDGE_LOOP('',(#976));
#978=FACE_BOUND('',#977,.T.);
#979=ADVANCED_FACE('F664',(#967,#978),#964,.F.);
#980=CARTESIAN_POINT('',(-80.0697340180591,44.45,-6.5676433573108));
#981=DIRECTION('',(0.,-1.,0.));
#982=DIRECTION('',(0.,0.,-1.));
#983=AXIS2_PLACEMENT_3D('',#980,#981,#982);
#984=PLANE('',#983);
#985=ORIENTED_EDGE('',*,*,#975,.F.);
#986=EDGE_LOOP('',(#985));
#987=FACE_BOUND('',#986,.T.);
#988=CARTESIAN_POINT('',(-82.7748340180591,44.45,-6.5676433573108));
#989=DIRECTION('',(0.,1.,0.));
#990=DIRECTION('',(0.,0.,1.));
#991=AXIS2_PLACEMENT_3D('',#988,#989,#990);
#992=CIRCLE('',#991,3.175);
#993=CARTESIAN_POINT('',(-82.7748340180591,44.45,-3.39264335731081));
#994=VERTEX_POINT('',#993);
#995=EDGE_CURVE('E347',#994,#994,#992,.T.);
#996=ORIENTED_EDGE('',*,*,#995,.T.);
#997=EDGE_LOOP('',(#996));
#998=FACE_BOUND('',#997,.T.);
#999=ADVANCED_FACE('F668',(#987,#998),#984,.F.);
#1000=CARTESIAN_POINT('',(-82.7748340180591,57.15,-6.5676433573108));
#1001=DIRECTION('',(0.,1.,0.));
#1002=DIRECTION('',(0.,0.,1.));
#1003=AXIS2_PLACEMENT_3D('',#1000,#1001,#1002);
#1004=CYLINDRICAL_SURFACE('',#1003,3.175);
#1005=ORIENTED_EDGE('',*,*,#995,.F.);
#1006=EDGE_LOOP('',(#1005));
#1007=FACE_BOUND('',#1006,.T.);
#1008=ORIENTED_EDGE('',*,*,#496,.T.);
#1009=EDGE_LOOP('',(#1008));
#1010=FACE_BOUND('',#1009,.T.);
#1011=ADVANCED_FACE('F672',(#1007,#1010),#1004,.F.);
#1012=CARTESIAN_POINT('',(-61.8041737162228,41.7297108,92.8445863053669));
#1013=DIRECTION('',(0.,1.,0.));
#1014=DIRECTION('',(0.,0.,1.));
#1015=AXIS2_PLACEMENT_3D('',#1012,#1013,#1014);
#1016=CONICAL_SURFACE('',#1015,2.70509999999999,1.02974425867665);
#1017=CARTESIAN_POINT('',(-61.8041737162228,40.1043227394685,92.8445863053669));
#1018=VERTEX_POINT('',#1017);
#1019=VERTEX_LOOP('',#1018);
#1020=FACE_BOUND('',#1019,.T.);
#1021=CARTESIAN_POINT('',(-61.8041737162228,41.7297108,92.8445863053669));
#1022=DIRECTION('',(0.,1.,0.));
#1023=DIRECTION('',(0.,0.,1.));
#1024=AXIS2_PLACEMENT_3D('',#1021,#1022,#1023);
#1025=CIRCLE('',#1024,2.70509999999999);
#1026=CARTESIAN_POINT('',(-61.8041737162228,41.7297108,95.5496863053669));
#1027=VERTEX_POINT('',#1026);
#1028=EDGE_CURVE('E341',#1027,#1027,#1025,.T.);
#1029=ORIENTED_EDGE('',*,*,#1028,.T.);
#1030=EDGE_LOOP('',(#1029));
#1031=FACE_BOUND('',#1030,.T.);
#1032=ADVANCED_FACE('F676',(#1020,#1031),#1016,.F.);
#1033=CARTESIAN_POINT('',(-61.8041737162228,57.15,92.8445863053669));
#1034=DIRECTION('',(0.,1.,0.));
#1035=DIRECTION('',(0.,0.,1.));
#1036=AXIS2_PLACEMENT_3D('',#1033,#1034,#1035);
#1037=CYLINDRICAL_SURFACE('',#1036,2.70509999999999);
#1038=ORIENTED_EDGE('',*,*,#1028,.F.);
#1039=EDGE_LOOP('',(#1038));
#1040=FACE_BOUND('',#1039,.T.);
#1041=CARTESIAN_POINT('',(-61.8041737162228,44.45,92.8445863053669));
#1042=DIRECTION('',(0.,1.,0.));
#1043=DIRECTION('',(0.,0.,1.));
#1044=AXIS2_PLACEMENT_3D('',#1041,#1042,#1043);
#1045=CIRCLE('',#1044,2.70509999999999);
#1046=CARTESIAN_POINT('',(-61.8041737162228,44.45,95.5496863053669));
#1047=VERTEX_POINT('',#1046);
#1048=EDGE_CURVE('E338',#1047,#1047,#1045,.T.);
#1049=ORIENTED_EDGE('',*,*,#1048,.T.);
#1050=EDGE_LOOP('',(#1049));
#1051=FACE_BOUND('',#1050,.T.);
#1052=ADVANCED_FACE('F680',(#1040,#1051),#1037,.F.);
#1053=CARTESIAN_POINT('',(-59.0990737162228,44.45,92.8445863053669));
#1054=DIRECTION('',(0.,-1.,0.));
#1055=DIRECTION('',(0.,0.,-1.));
#1056=AXIS2_PLACEMENT_3D('',#1053,#1054,#1055);
#1057=PLANE('',#1056);
#1058=ORIENTED_EDGE('',*,*,#1048,.F.);
#1059=EDGE_LOOP('',(#1058));
#1060=FACE_BOUND('',#1059,.T.);
#1061=CARTESIAN_POINT('',(-61.8041737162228,44.45,92.8445863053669));
#1062=DIRECTION('',(0.,1.,0.));
#1063=DIRECTION('',(0.,0.,1.));
#1064=AXIS2_PLACEMENT_3D('',#1061,#1062,#1063);
#1065=CIRCLE('',#1064,3.17499999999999);
#1066=CARTESIAN_POINT('',(-61.8041737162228,44.45,96.0195863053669));
#1067=VERTEX_POINT('',#1066);
#1068=EDGE_CURVE('E335',#1067,#1067,#1065,.T.);
#1069=ORIENTED_EDGE('',*,*,#1068,.T.);
#1070=EDGE_LOOP('',(#1069));
#1071=FACE_BOUND('',#1070,.T.);
#1072=ADVANCED_FACE('F684',(#1060,#1071),#1057,.F.);
#1073=CARTESIAN_POINT('',(-61.8041737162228,57.15,92.8445863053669));
#1074=DIRECTION('',(0.,1.,0.));
#1075=DIRECTION('',(0.,0.,1.));
#1076=AXIS2_PLACEMENT_3D('',#1073,#1074,#1075);
#1077=CYLINDRICAL_SURFACE('',#1076,3.17499999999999);
#1078=ORIENTED_EDGE('',*,*,#1068,.F.);
#1079=EDGE_LOOP('',(#1078));
#1080=FACE_BOUND('',#1079,.T.);
#1081=ORIENTED_EDGE('',*,*,#485,.T.);
#1082=EDGE_LOOP('',(#1081));
#1083=FACE_BOUND('',#1082,.T.);
#1084=ADVANCED_FACE('F688',(#1080,#1083),#1077,.F.);
#1085=CARTESIAN_POINT('',(63.4515482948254,41.7297108,107.767218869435));
#1086=DIRECTION('',(0.,1.,0.));
#1087=DIRECTION('',(0.,0.,1.));
#1088=AXIS2_PLACEMENT_3D('',#1085,#1086,#1087);
#1089=CONICAL_SURFACE('',#1088,2.7051,1.02974425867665);
#1090=CARTESIAN_POINT('',(63.4515482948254,40.1043227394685,107.767218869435));
#1091=VERTEX_POINT('',#1090);
#1092=VERTEX_LOOP('',#1091);
#1093=FACE_BOUND('',#1092,.T.);
#1094=CARTESIAN_POINT('',(63.4515482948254,41.7297108,107.767218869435));
#1095=DIRECTION('',(0.,1.,0.));
#1096=DIRECTION('',(0.,0.,1.));
#1097=AXIS2_PLACEMENT_3D('',#1094,#1095,#1096);
#1098=CIRCLE('',#1097,2.7051);
#1099=CARTESIAN_POINT('',(63.4515482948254,41.7297108,110.472318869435));
#1100=VERTEX_POINT('',#1099);
#1101=EDGE_CURVE('E329',#1100,#1100,#1098,.T.);
#1102=ORIENTED_EDGE('',*,*,#1101,.T.);
#1103=EDGE_LOOP('',(#1102));
#1104=FACE_BOUND('',#1103,.T.);
#1105=ADVANCED_FACE('F692',(#1093,#1104),#1089,.F.);
#1106=CARTESIAN_POINT('',(63.4515482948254,57.15,107.767218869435));
#1107=DIRECTION('',(0.,1.,0.));
#1108=DIRECTION('',(0.,0.,1.));
#1109=AXIS2_PLACEMENT_3D('',#1106,#1107,#1108);
#1110=CYLINDRICAL_SURFACE('',#1109,2.70509999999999);
#1111=ORIENTED_EDGE('',*,*,#1101,.F.);
#1112=EDGE_LOOP('',(#1111));
#1113=FACE_BOUND('',#1112,.T.);
#1114=CARTESIAN_POINT('',(63.4515482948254,44.45,107.767218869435));
#1115=DIRECTION('',(0.,1.,0.));
#1116=DIRECTION('',(0.,0.,1.));
#1117=AXIS2_PLACEMENT_3D('',#1114,#1115,#1116);
#1118=CIRCLE('',#1117,2.70509999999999);
#1119=CARTESIAN_POINT('',(63.4515482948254,44.45,110.472318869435));
#1120=VERTEX_POINT('',#1119);
#1121=EDGE_CURVE('E326',#1120,#1120,#1118,.T.);
#1122=ORIENTED_EDGE('',*,*,#1121,.T.);
#1123=EDGE_LOOP('',(#1122));
#1124=FACE_BOUND('',#1123,.T.);
#1125=ADVANCED_FACE('F696',(#1113,#1124),#1110,.F.);
#1126=CARTESIAN_POINT('',(66.1566482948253,44.45,107.767218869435));
#1127=DIRECTION('',(0.,-1.,0.));
#1128=DIRECTION('',(0.,0.,-1.));
#1129=AXIS2_PLACEMENT_3D('',#1126,#1127,#1128);
#1130=PLANE('',#1129);
#1131=ORIENTED_EDGE('',*,*,#1121,.F.);
#1132=EDGE_LOOP('',(#1131));
#1133=FACE_BOUND('',#1132,.T.);
#1134=CARTESIAN_POINT('',(63.4515482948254,44.45,107.767218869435));
#1135=DIRECTION('',(0.,1.,0.));
#1136=DIRECTION('',(0.,0.,1.));
#1137=AXIS2_PLACEMENT_3D('',#1134,#1135,#1136);
#1138=CIRCLE('',#1137,3.17499999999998);
#1139=CARTESIAN_POINT('',(63.4515482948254,44.45,110.942218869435));
#1140=VERTEX_POINT('',#1139);
#1141=EDGE_CURVE('E323',#1140,#1140,#1138,.T.);
#1142=ORIENTED_EDGE('',*,*,#1141,.T.);
#1143=EDGE_LOOP('',(#1142));
#1144=FACE_BOUND('',#1143,.T.);
#1145=ADVANCED_FACE('F700',(#1133,#1144),#1130,.F.);
#1146=CARTESIAN_POINT('',(63.4515482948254,57.15,107.767218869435));
#1147=DIRECTION('',(0.,1.,0.));
#1148=DIRECTION('',(0.,0.,1.));
#1149=AXIS2_PLACEMENT_3D('',#1146,#1147,#1148);
#1150=CYLINDRICAL_SURFACE('',#1149,3.17499999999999);
#1151=ORIENTED_EDGE('',*,*,#1141,.F.);
#1152=EDGE_LOOP('',(#1151));
#1153=FACE_BOUND('',#1152,.T.);
#1154=ORIENTED_EDGE('',*,*,#474,.T.);
#1155=EDGE_LOOP('',(#1154));
#1156=FACE_BOUND('',#1155,.T.);
#1157=ADVANCED_FACE('F704',(#1153,#1156),#1150,.F.);
#1158=CARTESIAN_POINT('',(88.7462441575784,41.7297108,9.3663125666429));
#1159=DIRECTION('',(0.,1.,0.));
#1160=DIRECTION('',(0.,0.,1.));
#1161=AXIS2_PLACEMENT_3D('',#1158,#1159,#1160);
#1162=CONICAL_SURFACE('',#1161,2.7051,1.02974425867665);
#1163=CARTESIAN_POINT('',(88.7462441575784,40.1043227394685,9.3663125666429));
#1164=VERTEX_POINT('',#1163);
#1165=VERTEX_LOOP('',#1164);
#1166=FACE_BOUND('',#1165,.T.);
#1167=CARTESIAN_POINT('',(88.7462441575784,41.7297108,9.3663125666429));
#1168=DIRECTION('',(0.,1.,0.));
#1169=DIRECTION('',(0.,0.,1.));
#1170=AXIS2_PLACEMENT_3D('',#1167,#1168,#1169);
#1171=CIRCLE('',#1170,2.7051);
#1172=CARTESIAN_POINT('',(88.7462441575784,41.7297108,12.0714125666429));
#1173=VERTEX_POINT('',#1172);
#1174=EDGE_CURVE('E317',#1173,#1173,#1171,.T.);
#1175=ORIENTED_EDGE('',*,*,#1174,.T.);
#1176=EDGE_LOOP('',(#1175));
#1177=FACE_BOUND('',#1176,.T.);
#1178=ADVANCED_FACE('F708',(#1166,#1177),#1162,.F.);
#1179=CARTESIAN_POINT('',(88.7462441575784,57.15,9.3663125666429));
#1180=DIRECTION('',(0.,1.,0.));
#1181=DIRECTION('',(0.,0.,1.));
#1182=AXIS2_PLACEMENT_3D('',#1179,#1180,#1181);
#1183=CYLINDRICAL_SURFACE('',#1182,2.70509999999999);
#1184=ORIENTED_EDGE('',*,*,#1174,.F.);
#1185=EDGE_LOOP('',(#1184));
#1186=FACE_BOUND('',#1185,.T.);
#1187=CARTESIAN_POINT('',(88.7462441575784,44.45,9.3663125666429));
#1188=DIRECTION('',(0.,1.,0.));
#1189=DIRECTION('',(0.,0.,1.));
#1190=AXIS2_PLACEMENT_3D('',#1187,#1188,#1189);
#1191=CIRCLE('',#1190,2.70509999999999);
#1192=CARTESIAN_POINT('',(88.7462441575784,44.45,12.0714125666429));
#1193=VERTEX_POINT('',#1192);
#1194=EDGE_CURVE('E314',#1193,#1193,#1191,.T.);
#1195=ORIENTED_EDGE('',*,*,#1194,.T.);
#1196=EDGE_LOOP('',(#1195));
#1197=FACE_BOUND('',#1196,.T.);
#1198=ADVANCED_FACE('F712',(#1186,#1197),#1183,.F.);
#1199=CARTESIAN_POINT('',(91.4513441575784,44.45,9.3663125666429));
#1200=DIRECTION('',(0.,-1.,0.));
#1201=DIRECTION('',(0.,0.,-1.));
#1202=AXIS2_PLACEMENT_3D('',#1199,#1200,#1201);
#1203=PLANE('',#1202);
#1204=ORIENTED_EDGE('',*,*,#1194,.F.);
#1205=EDGE_LOOP('',(#1204));
#1206=FACE_BOUND('',#1205,.T.);
#1207=CARTESIAN_POINT('',(88.7462441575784,44.45,9.3663125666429));
#1208=DIRECTION('',(0.,1.,0.));
#1209=DIRECTION('',(0.,0.,1.));
#1210=AXIS2_PLACEMENT_3D('',#1207,#1208,#1209);
#1211=CIRCLE('',#1210,3.17499999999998);
#1212=CARTESIAN_POINT('',(88.7462441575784,44.45,12.5413125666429));
#1213=VERTEX_POINT('',#1212);
#1214=EDGE_CURVE('E311',#1213,#1213,#1211,.T.);
#1215=ORIENTED_EDGE('',*,*,#1214,.T.);
#1216=EDGE_LOOP('',(#1215));
#1217=FACE_BOUND('',#1216,.T.);
#1218=ADVANCED_FACE('F716',(#1206,#1217),#1203,.F.);
#1219=CARTESIAN_POINT('',(88.7462441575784,57.15,9.3663125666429));
#1220=DIRECTION('',(0.,1.,0.));
#1221=DIRECTION('',(0.,0.,1.));
#1222=AXIS2_PLACEMENT_3D('',#1219,#1220,#1221);
#1223=CYLINDRICAL_SURFACE('',#1222,3.17499999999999);
#1224=ORIENTED_EDGE('',*,*,#1214,.F.);
#1225=EDGE_LOOP('',(#1224));
#1226=FACE_BOUND('',#1225,.T.);
#1227=ORIENTED_EDGE('',*,*,#463,.T.);
#1228=EDGE_LOOP('',(#1227));
#1229=FACE_BOUND('',#1228,.T.);
#1230=ADVANCED_FACE('F720',(#1226,#1229),#1223,.F.);
#1231=CARTESIAN_POINT('',(50.8,41.7297108,-141.324774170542));
#1232=DIRECTION('',(0.,1.,0.));
#1233=DIRECTION('',(0.,0.,1.));
#1234=AXIS2_PLACEMENT_3D('',#1231,#1232,#1233);
#1235=CONICAL_SURFACE('',#1234,2.70509999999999,1.02974425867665);
#1236=CARTESIAN_POINT('',(50.8,40.1043227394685,-141.324774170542));
#1237=VERTEX_POINT('',#1236);
#1238=VERTEX_LOOP('',#1237);
#1239=FACE_BOUND('',#1238,.T.);
#1240=CARTESIAN_POINT('',(50.8,41.7297108,-141.324774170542));
#1241=DIRECTION('',(0.,1.,0.));
#1242=DIRECTION('',(0.,0.,1.));
#1243=AXIS2_PLACEMENT_3D('',#1240,#1241,#1242);
#1244=CIRCLE('',#1243,2.70509999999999);
#1245=CARTESIAN_POINT('',(50.8,41.7297108,-138.619674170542));
#1246=VERTEX_POINT('',#1245);
#1247=EDGE_CURVE('E305',#1246,#1246,#1244,.T.);
#1248=ORIENTED_EDGE('',*,*,#1247,.T.);
#1249=EDGE_LOOP('',(#1248));
#1250=FACE_BOUND('',#1249,.T.);
#1251=ADVANCED_FACE('F724',(#1239,#1250),#1235,.F.);
#1252=CARTESIAN_POINT('',(50.8,57.15,-141.324774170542));
#1253=DIRECTION('',(0.,1.,0.));
#1254=DIRECTION('',(0.,0.,1.));
#1255=AXIS2_PLACEMENT_3D('',#1252,#1253,#1254);
#1256=CYLINDRICAL_SURFACE('',#1255,2.70509999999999);
#1257=ORIENTED_EDGE('',*,*,#1247,.F.);
#1258=EDGE_LOOP('',(#1257));
#1259=FACE_BOUND('',#1258,.T.);
#1260=CARTESIAN_POINT('',(50.8,44.45,-141.324774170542));
#1261=DIRECTION('',(0.,1.,0.));
#1262=DIRECTION('',(0.,0.,1.));
#1263=AXIS2_PLACEMENT_3D('',#1260,#1261,#1262);
#1264=CIRCLE('',#1263,2.70509999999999);
#1265=CARTESIAN_POINT('',(50.8,44.45,-138.619674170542));
#1266=VERTEX_POINT('',#1265);
#1267=EDGE_CURVE('E302',#1266,#1266,#1264,.T.);
#1268=ORIENTED_EDGE('',*,*,#1267,.T.);
#1269=EDGE_LOOP('',(#1268));
#1270=FACE_BOUND('',#1269,.T.);
#1271=ADVANCED_FACE('F728',(#1259,#1270),#1256,.F.);
#1272=CARTESIAN_POINT('',(53.5051,44.45,-141.324774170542));
#1273=DIRECTION('',(0.,-1.,0.));
#1274=DIRECTION('',(0.,0.,-1.));
#1275=AXIS2_PLACEMENT_3D('',#1272,#1273,#1274);
#1276=PLANE('',#1275);
#1277=ORIENTED_EDGE('',*,*,#1267,.F.);
#1278=EDGE_LOOP('',(#1277));
#1279=FACE_BOUND('',#1278,.T.);
#1280=CARTESIAN_POINT('',(50.8,44.45,-141.324774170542));
#1281=DIRECTION('',(0.,1.,0.));
#1282=DIRECTION('',(0.,0.,1.));
#1283=AXIS2_PLACEMENT_3D('',#1280,#1281,#1282);
#1284=CIRCLE('',#1283,3.17499999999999);
#1285=CARTESIAN_POINT('',(50.8,44.45,-138.149774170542));
#1286=VERTEX_POINT('',#1285);
#1287=EDGE_CURVE('E293',#1286,#1286,#1284,.T.);
#1288=ORIENTED_EDGE('',*,*,#1287,.T.);
#1289=EDGE_LOOP('',(#1288));
#1290=FACE_BOUND('',#1289,.T.);
#1291=ADVANCED_FACE('F732',(#1279,#1290),#1276,.F.);
#1292=CARTESIAN_POINT('',(50.8,57.15,-141.324774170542));
#1293=DIRECTION('',(0.,1.,0.));
#1294=DIRECTION('',(0.,0.,1.));
#1295=AXIS2_PLACEMENT_3D('',#1292,#1293,#1294);
#1296=CYLINDRICAL_SURFACE('',#1295,3.17499999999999);
#1297=ORIENTED_EDGE('',*,*,#1287,.F.);
#1298=EDGE_LOOP('',(#1297));
#1299=FACE_BOUND('',#1298,.T.);
#1300=ORIENTED_EDGE('',*,*,#452,.T.);
#1301=EDGE_LOOP('',(#1300));
#1302=FACE_BOUND('',#1301,.T.);
#1303=ADVANCED_FACE('F283',(#1299,#1302),#1296,.F.);
#1304=CARTESIAN_POINT('',(-50.8,41.7297108,-141.324774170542));
#1305=DIRECTION('',(0.,1.,0.));
#1306=DIRECTION('',(0.,0.,1.));
#1307=AXIS2_PLACEMENT_3D('',#1304,#1305,#1306);
#1308=CONICAL_SURFACE('',#1307,2.70509999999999,1.02974425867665);
#1309=CARTESIAN_POINT('',(-50.8,40.1043227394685,-141.324774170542));
#1310=VERTEX_POINT('',#1309);
#1311=VERTEX_LOOP('',#1310);
#1312=FACE_BOUND('',#1311,.T.);
#1313=CARTESIAN_POINT('',(-50.8,41.7297108,-141.324774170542));
#1314=DIRECTION('',(0.,1.,0.));
#1315=DIRECTION('',(0.,0.,1.));
#1316=AXIS2_PLACEMENT_3D('',#1313,#1314,#1315);
#1317=CIRCLE('',#1316,2.70509999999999);
#1318=CARTESIAN_POINT('',(-50.8,41.7297108,-138.619674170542));
#1319=VERTEX_POINT('',#1318);
#1320=EDGE_CURVE('E287',#1319,#1319,#1317,.T.);
#1321=ORIENTED_EDGE('',*,*,#1320,.T.);
#1322=EDGE_LOOP('',(#1321));
#1323=FACE_BOUND('',#1322,.T.);
#1324=ADVANCED_FACE('F279',(#1312,#1323),#1308,.F.);
#1325=CARTESIAN_POINT('',(-50.8,57.15,-141.324774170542));
#1326=DIRECTION('',(0.,1.,0.));
#1327=DIRECTION('',(0.,0.,1.));
#1328=AXIS2_PLACEMENT_3D('',#1325,#1326,#1327);
#1329=CYLINDRICAL_SURFACE('',#1328,2.70509999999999);
#1330=ORIENTED_EDGE('',*,*,#1320,.F.);
#1331=EDGE_LOOP('',(#1330));
#1332=FACE_BOUND('',#1331,.T.);
#1333=CARTESIAN_POINT('',(-50.8,44.45,-141.324774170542));
#1334=DIRECTION('',(0.,1.,0.));
#1335=DIRECTION('',(0.,0.,1.));
#1336=AXIS2_PLACEMENT_3D('',#1333,#1334,#1335);
#1337=CIRCLE('',#1336,2.70509999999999);
#1338=CARTESIAN_POINT('',(-50.8,44.45,-138.619674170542));
#1339=VERTEX_POINT('',#1338);
#1340=EDGE_CURVE('E290',#1339,#1339,#1337,.T.);
#1341=ORIENTED_EDGE('',*,*,#1340,.T.);
#1342=EDGE_LOOP('',(#1341));
#1343=FACE_BOUND('',#1342,.T.);
#1344=ADVANCED_FACE('F282',(#1332,#1343),#1329,.F.);
#1345=CARTESIAN_POINT('',(-48.0949,44.45,-141.324774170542));
#1346=DIRECTION('',(0.,-1.,0.));
#1347=DIRECTION('',(0.,0.,-1.));
#1348=AXIS2_PLACEMENT_3D('',#1345,#1346,#1347);
#1349=PLANE('',#1348);
#1350=ORIENTED_EDGE('',*,*,#1340,.F.);
#1351=EDGE_LOOP('',(#1350));
#1352=FACE_BOUND('',#1351,.T.);
#1353=CARTESIAN_POINT('',(-50.8,44.45,-141.324774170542));
#1354=DIRECTION('',(0.,1.,0.));
#1355=DIRECTION('',(0.,0.,1.));
#1356=AXIS2_PLACEMENT_3D('',#1353,#1354,#1355);
#1357=CIRCLE('',#1356,3.17499999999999);
#1358=CARTESIAN_POINT('',(-50.8,44.45,-138.149774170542));
#1359=VERTEX_POINT('',#1358);
#1360=EDGE_CURVE('E296',#1359,#1359,#1357,.T.);
#1361=ORIENTED_EDGE('',*,*,#1360,.T.);
#1362=EDGE_LOOP('',(#1361));
#1363=FACE_BOUND('',#1362,.T.);
#1364=ADVANCED_FACE('F742',(#1352,#1363),#1349,.F.);
#1365=CARTESIAN_POINT('',(-50.8,57.15,-141.324774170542));
#1366=DIRECTION('',(0.,1.,0.));
#1367=DIRECTION('',(0.,0.,1.));
#1368=AXIS2_PLACEMENT_3D('',#1365,#1366,#1367);
#1369=CYLINDRICAL_SURFACE('',#1368,3.17499999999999);
#1370=ORIENTED_EDGE('',*,*,#1360,.F.);
#1371=EDGE_LOOP('',(#1370));
#1372=FACE_BOUND('',#1371,.T.);
#1373=ORIENTED_EDGE('',*,*,#441,.T.);
#1374=EDGE_LOOP('',(#1373));
#1375=FACE_BOUND('',#1374,.T.);
#1376=ADVANCED_FACE('F745',(#1372,#1375),#1369,.F.);
#1377=CLOSED_SHELL('',(#60,#93,#126,#157,#190,#223,#256,#287,#320,#353,#386,#408,#428,#621,#653,
#678,#702,#727,#752,#777,#801,#826,#851,#876,#900,#918,#938,#959,#979,#999,#1011,#1032,#1052,
#1072,#1084,#1105,#1125,#1145,#1157,#1178,#1198,#1218,#1230,#1251,#1271,#1291,#1303,#1324,#1344,
#1364,#1376));
#1378=MANIFOLD_SOLID_BREP('B2',#1377);
#1379=ADVANCED_BREP_SHAPE_REPRESENTATION('',(#18,#1378),#14);
#1380=SHAPE_DEFINITION_REPRESENTATION(#9,#1379);
ENDSEC;
END-ISO-10303-21;
